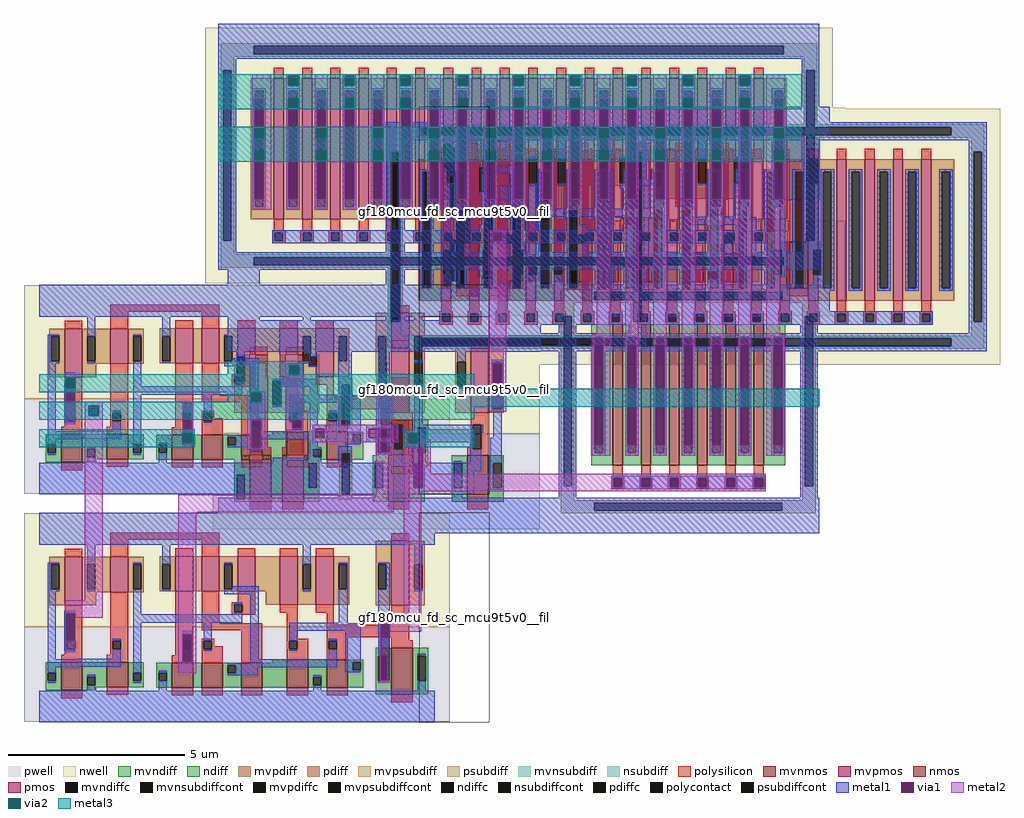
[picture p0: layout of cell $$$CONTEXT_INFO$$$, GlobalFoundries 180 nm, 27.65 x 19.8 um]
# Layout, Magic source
magic
tech gf180mcuD
magscale 1 10
use dff_2ph_clk$1  dff_2ph_clk$1_0
transform 1 0 0 0 1 0
box -2326 -2405 310 103
use gf180mcu_fd_sc_mcu9t5v0__fill_2  gf180mcu_fd_sc_mcu9t5v0__fill_2_0
transform 1 0 0 0 1 0
box -86 -90 310 1098
use gf180mcu_fd_sc_mcu9t5v0__filltie$1  gf180mcu_fd_sc_mcu9t5v0__filltie$1_0
transform 1 0 0 0 1 0
box -86 -90 310 1098
use gf180mcu_fd_sc_mcu9t5v0__filltie  gf180mcu_fd_sc_mcu9t5v0__filltie_0
transform 1 0 0 0 1 0
box -86 -90 310 1098
use gf180mcu_fd_sc_mcu9t5v0__inv_1  gf180mcu_fd_sc_mcu9t5v0__inv_1_0
transform 1 0 0 0 1 0
box -86 -90 534 1098
use gf180mcu_fd_sc_mcu9t5v0__latq_1  gf180mcu_fd_sc_mcu9t5v0__latq_1_0
transform 1 0 0 0 1 0
box -86 -90 2326 1098
use gf180mcu_fd_sc_mcu9t5v0__nand2_1  gf180mcu_fd_sc_mcu9t5v0__nand2_1_0
transform 1 0 0 0 1 0
box -86 -90 646 1098
use nfet  nfet_0
transform 1 0 0 0 1 0
box -268 -284 1200 1010
use pfet  pfet_0
transform 1 0 0 0 1 0
box -352 -362 3204 1086
use tgate$1  tgate$1_0
transform 1 0 0 0 1 0
box -1300 -1318 2256 1570
<< end >>

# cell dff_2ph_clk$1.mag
magic
tech gf180mcuD
magscale 1 10
<< metal1 >>
rect -2240 -90 224 90
rect -2240 -1098 224 -918
<< via1 >>
rect -2089 -635 -2037 -479
rect -1427 -754 -1375 -598
rect -306 -860 -254 -496
rect -2089 -1927 -2037 -1771
rect -1427 -2046 -1375 -1890
rect -306 -2152 -254 -1788
<< metal2 >>
rect -2093 -440 -2037 -406
rect -2093 -496 -2091 -440
rect -330 -496 -230 -484
rect -2093 -635 -2089 -496
rect -2093 -701 -2037 -635
rect -1981 -596 -1881 -574
rect -1981 -652 -1959 -596
rect -1903 -652 -1881 -596
rect -1981 -1698 -1881 -652
rect -1427 -598 -1371 -585
rect -1375 -752 -1371 -598
rect -1373 -808 -1371 -752
rect -1427 -820 -1371 -808
rect -330 -860 -306 -496
rect -254 -860 -230 -496
rect -330 -1100 -230 -860
rect -2093 -1771 -1881 -1698
rect -2093 -1927 -2089 -1771
rect -2037 -1798 -1881 -1771
rect -1451 -1200 -230 -1100
rect -174 -752 -74 -730
rect -174 -808 -152 -752
rect -96 -808 -74 -752
rect -2093 -1993 -2037 -1927
rect -1451 -1890 -1351 -1200
rect -174 -1776 -74 -808
rect -1451 -2046 -1427 -1890
rect -1375 -2046 -1351 -1890
rect -1451 -2112 -1351 -2046
rect -310 -1788 -74 -1776
rect -310 -2152 -306 -1788
rect -254 -1876 -74 -1788
rect -310 -2164 -254 -2152
<< via2 >>
rect -2091 -479 -2035 -440
rect -2091 -496 -2089 -479
rect -2089 -496 -2037 -479
rect -2037 -496 -2035 -479
rect -1959 -652 -1903 -596
rect -1429 -754 -1427 -752
rect -1427 -754 -1375 -752
rect -1375 -754 -1373 -752
rect -1429 -808 -1373 -754
rect -152 -808 -96 -752
<< metal3 >>
rect -2241 -440 224 -418
rect -2241 -496 -2091 -440
rect -2035 -496 224 -440
rect -2241 -518 224 -496
rect -2241 -596 224 -574
rect -2241 -652 -1959 -596
rect -1903 -652 224 -596
rect -2241 -674 224 -652
rect -2241 -752 -1359 -730
rect -2241 -808 -1429 -752
rect -1373 -808 -1359 -752
rect -2241 -830 -1359 -808
rect -174 -752 224 -730
rect -174 -808 -152 -752
rect -96 -808 224 -752
rect -174 -830 224 -808
use gf180mcu_fd_sc_mcu9t5v0__filltie$1  gf180mcu_fd_sc_mcu9t5v0__filltie$1_0
transform 1 0 0 0 1 -2300
box -86 -90 310 1098
use gf180mcu_fd_sc_mcu9t5v0__filltie$1  gf180mcu_fd_sc_mcu9t5v0__filltie$1_1
transform 1 0 0 0 1 -1008
box -86 -90 310 1098
use gf180mcu_fd_sc_mcu9t5v0__latq_1  gf180mcu_fd_sc_mcu9t5v0__latq_1_0
transform 1 0 -2240 0 1 -2300
box -86 -90 2326 1098
use gf180mcu_fd_sc_mcu9t5v0__latq_1  gf180mcu_fd_sc_mcu9t5v0__latq_1_1
transform 1 0 -2240 0 1 -1008
box -86 -90 2326 1098
<< labels >>
flabel metal1 s -2237 -2389 -2237 -2389 2 FreeSans 73 0 0 0 VSSD
port 1 nsew
flabel metal1 s -2237 -1205 -2237 -1205 4 FreeSans 73 0 0 0 VDDD
port 2 nsew
flabel metal1 s -2238 -1096 -2238 -1096 2 FreeSans 73 0 0 0 VSSD
port 1 nsew
flabel metal1 s -2238 88 -2238 88 4 FreeSans 73 0 0 0 VDDD
port 2 nsew
flabel metal3 s 221 -780 221 -780 8 FreeSans 89 0 0 0 Q
port 3 nsew
flabel metal3 s -2239 -468 -2239 -468 2 FreeSans 89 0 0 0 CLK_PH1
port 4 nsew
flabel metal3 s -2239 -624 -2239 -624 2 FreeSans 89 0 0 0 CLK_PH2
port 5 nsew
flabel metal3 s -2239 -780 -2239 -780 2 FreeSans 89 0 0 0 D
port 6 nsew
<< properties >>
string path -11.205 -2.340 1.120 -2.340 
<< end >>

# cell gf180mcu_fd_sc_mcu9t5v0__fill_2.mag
magic
tech gf180mcuD
magscale 1 10
<< nwell >>
rect -86 453 310 1094
<< pwell >>
rect -86 -86 310 453
<< metal1 >>
rect 0 918 224 1098
rect 0 -90 224 90
<< labels >>
flabel metal1 s 102 1000 102 1000 0 FreeSans 400 0 0 0 VDD
port 1 nsew
flabel metal1 s 104 0 104 0 0 FreeSans 400 0 0 0 VSS
port 2 nsew
flabel nwell s 69 784 69 784 0 FreeSans 400 0 0 0 VNW
port 3 nsew
flabel pwell s 68 -17 68 -17 0 FreeSans 400 0 0 0 VPW
port 4 nsew
<< properties >>
string FIXED_BBOX 0 0 224 1008
<< end >>

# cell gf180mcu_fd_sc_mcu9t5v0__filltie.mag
magic
tech gf180mcuD
magscale 1 10
<< nwell >>
rect -86 453 310 1094
<< pwell >>
rect -86 -86 310 453
<< mvpsubdiff >>
rect 72 344 144 357
rect 72 110 85 344
rect 131 110 144 344
rect 72 82 144 110
<< mvnsubdiff >>
rect 72 732 144 771
rect 72 498 85 732
rect 131 498 144 732
rect 72 485 144 498
<< mvpsubdiffcont >>
rect 85 110 131 344
<< mvnsubdiffcont >>
rect 85 498 131 732
<< metal1 >>
rect 0 918 224 1098
rect 66 732 142 918
rect 66 498 85 732
rect 131 498 142 732
rect 66 468 142 498
rect 66 344 142 382
rect 66 110 85 344
rect 131 110 142 344
rect 66 90 142 110
rect 0 -90 224 90
<< labels >>
flabel metal1 s 112 -90 112 -90 0 FreeSans 200 0 0 0 VSS
port 1 nsew
flabel metal1 s 112 1098 112 1098 0 FreeSans 200 0 0 0 VDD
port 2 nsew
<< properties >>
string FIXED_BBOX 0 0 224 1008
<< end >>

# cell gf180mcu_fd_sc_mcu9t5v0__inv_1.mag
magic
tech gf180mcuD
magscale 1 10
<< nwell >>
rect -86 453 534 1094
<< pwell >>
rect -86 -86 534 453
<< mvnmos >>
rect 124 69 244 333
<< mvpmos >>
rect 144 573 244 939
<< mvndiff >>
rect 36 287 124 333
rect 36 147 49 287
rect 95 147 124 287
rect 36 69 124 147
rect 244 287 332 333
rect 244 147 273 287
rect 319 147 332 287
rect 244 69 332 147
<< mvpdiff >>
rect 56 861 144 939
rect 56 721 69 861
rect 115 721 144 861
rect 56 573 144 721
rect 244 861 332 939
rect 244 721 273 861
rect 319 721 332 861
rect 244 573 332 721
<< mvndiffc >>
rect 49 147 95 287
rect 273 147 319 287
<< mvpdiffc >>
rect 69 721 115 861
rect 273 721 319 861
<< polysilicon >>
rect 144 939 244 983
rect 144 506 244 573
rect 144 377 157 506
rect 124 366 157 377
rect 203 366 244 506
rect 124 333 244 366
rect 124 25 244 69
<< polycontact >>
rect 157 366 203 506
<< metal1 >>
rect 0 918 448 1098
rect 69 861 115 918
rect 69 710 115 721
rect 273 861 319 872
rect 142 366 157 506
rect 203 460 214 506
rect 273 430 319 721
rect 49 287 95 298
rect 142 242 203 366
rect 254 287 319 430
rect 49 90 95 147
rect 254 147 273 287
rect 254 136 319 147
rect 0 -90 448 90
<< labels >>
flabel metal1 s 168 392 168 392 0 FreeSans 200 0 0 0 I
port 1 nsew
flabel metal1 s 224 1098 224 1098 0 FreeSans 200 0 0 0 VDD
port 2 nsew
flabel metal1 s 224 -90 224 -90 0 FreeSans 200 0 0 0 VSS
port 3 nsew
flabel metal1 s 280 392 280 392 0 FreeSans 200 0 0 0 ZN
port 4 nsew
flabel nwell s 69 784 69 784 0 FreeSans 400 0 0 0 VNW
port 5 nsew
flabel pwell s 68 -17 68 -17 0 FreeSans 400 0 0 0 VPW
port 6 nsew
<< properties >>
string FIXED_BBOX 0 0 448 1008
<< end >>

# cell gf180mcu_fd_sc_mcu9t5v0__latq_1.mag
magic
tech gf180mcuD
magscale 1 10
<< nwell >>
rect -86 453 2326 1094
<< pwell >>
rect -86 -86 2326 453
<< mvnmos >>
rect 124 92 244 250
rect 384 110 504 250
rect 752 107 872 247
rect 920 107 1040 247
rect 1144 107 1264 247
rect 1404 107 1524 265
rect 1628 107 1748 265
rect 1996 69 2116 333
<< mvpmos >>
rect 144 573 244 849
rect 404 649 504 849
rect 772 652 872 852
rect 920 652 1020 852
rect 1124 652 1224 852
rect 1364 576 1464 852
rect 1568 576 1668 852
rect 1996 573 2096 939
<< mvndiff >>
rect 36 193 124 250
rect 36 147 49 193
rect 95 147 124 193
rect 36 92 124 147
rect 244 168 384 250
rect 244 122 273 168
rect 319 122 384 168
rect 244 110 384 122
rect 504 193 592 250
rect 1908 287 1996 333
rect 1324 247 1404 265
rect 504 147 533 193
rect 579 147 592 193
rect 504 110 592 147
rect 664 193 752 247
rect 664 147 677 193
rect 723 147 752 193
rect 244 92 324 110
rect 664 107 752 147
rect 872 107 920 247
rect 1040 234 1144 247
rect 1040 188 1069 234
rect 1115 188 1144 234
rect 1040 107 1144 188
rect 1264 107 1404 247
rect 1524 166 1628 265
rect 1524 120 1553 166
rect 1599 120 1628 166
rect 1524 107 1628 120
rect 1748 252 1836 265
rect 1748 206 1777 252
rect 1823 206 1836 252
rect 1748 107 1836 206
rect 1908 147 1921 287
rect 1967 147 1996 287
rect 1908 69 1996 147
rect 2116 287 2204 333
rect 2116 147 2145 287
rect 2191 147 2204 287
rect 2116 69 2204 147
<< mvpdiff >>
rect 56 805 144 849
rect 56 665 69 805
rect 115 665 144 805
rect 56 573 144 665
rect 244 805 404 849
rect 244 665 273 805
rect 319 665 404 805
rect 244 649 404 665
rect 504 805 592 849
rect 504 665 533 805
rect 579 665 592 805
rect 504 649 592 665
rect 684 805 772 852
rect 684 665 697 805
rect 743 665 772 805
rect 684 652 772 665
rect 872 652 920 852
rect 1020 805 1124 852
rect 1020 665 1049 805
rect 1095 665 1124 805
rect 1020 652 1124 665
rect 1224 652 1364 852
rect 244 573 324 649
rect 1284 576 1364 652
rect 1464 805 1568 852
rect 1464 665 1493 805
rect 1539 665 1568 805
rect 1464 576 1568 665
rect 1668 805 1756 852
rect 1668 665 1697 805
rect 1743 665 1756 805
rect 1668 576 1756 665
rect 1908 805 1996 939
rect 1908 665 1921 805
rect 1967 665 1996 805
rect 1908 573 1996 665
rect 2096 805 2184 939
rect 2096 665 2125 805
rect 2171 665 2184 805
rect 2096 573 2184 665
<< mvndiffc >>
rect 49 147 95 193
rect 273 122 319 168
rect 533 147 579 193
rect 677 147 723 193
rect 1069 188 1115 234
rect 1553 120 1599 166
rect 1777 206 1823 252
rect 1921 147 1967 287
rect 2145 147 2191 287
<< mvpdiffc >>
rect 69 665 115 805
rect 273 665 319 805
rect 533 665 579 805
rect 697 665 743 805
rect 1049 665 1095 805
rect 1493 665 1539 805
rect 1697 665 1743 805
rect 1921 665 1967 805
rect 2125 665 2171 805
<< polysilicon >>
rect 404 944 1020 984
rect 144 849 244 893
rect 404 849 504 944
rect 772 852 872 896
rect 920 852 1020 944
rect 1996 939 2096 983
rect 1124 852 1224 896
rect 1364 852 1464 896
rect 1568 852 1668 896
rect 144 372 244 573
rect 144 326 157 372
rect 203 326 244 372
rect 144 294 244 326
rect 404 372 504 649
rect 404 326 417 372
rect 463 326 504 372
rect 404 294 504 326
rect 124 250 244 294
rect 384 250 504 294
rect 772 372 872 652
rect 920 472 1020 652
rect 1124 608 1224 652
rect 1124 592 1223 608
rect 1092 579 1223 592
rect 1092 533 1105 579
rect 1151 533 1223 579
rect 1092 520 1223 533
rect 1364 532 1464 576
rect 1568 532 1668 576
rect 920 433 1264 472
rect 1011 432 1264 433
rect 772 326 813 372
rect 859 326 872 372
rect 772 291 872 326
rect 752 247 872 291
rect 920 372 992 385
rect 920 326 933 372
rect 979 343 992 372
rect 979 326 1040 343
rect 920 247 1040 326
rect 1144 247 1264 432
rect 1404 385 1464 532
rect 1628 465 1668 532
rect 1996 465 2096 573
rect 1628 393 2096 465
rect 1404 372 1524 385
rect 1404 326 1417 372
rect 1463 326 1524 372
rect 1404 265 1524 326
rect 1628 372 1748 393
rect 1628 326 1641 372
rect 1687 326 1748 372
rect 1996 377 2096 393
rect 1996 333 2116 377
rect 1628 265 1748 326
rect 124 48 244 92
rect 384 66 504 110
rect 752 63 872 107
rect 920 63 1040 107
rect 1144 63 1264 107
rect 1404 63 1524 107
rect 1628 63 1748 107
rect 1996 25 2116 69
<< polycontact >>
rect 157 326 203 372
rect 417 326 463 372
rect 1105 533 1151 579
rect 813 326 859 372
rect 933 326 979 372
rect 1417 326 1463 372
rect 1641 326 1687 372
<< metal1 >>
rect 0 918 2240 1098
rect 49 805 115 816
rect 49 665 69 805
rect 49 654 115 665
rect 273 805 319 918
rect 273 654 319 665
rect 533 805 579 816
rect 49 269 95 654
rect 142 372 203 542
rect 533 522 579 665
rect 697 805 743 918
rect 697 654 743 665
rect 1049 805 1095 816
rect 1493 805 1539 918
rect 1095 665 1243 682
rect 1049 636 1243 665
rect 1493 654 1539 665
rect 1697 805 1747 816
rect 1743 665 1747 805
rect 1105 579 1151 590
rect 1105 522 1151 533
rect 533 476 1151 522
rect 142 326 157 372
rect 142 315 203 326
rect 417 372 463 383
rect 417 271 463 326
rect 217 269 463 271
rect 49 225 463 269
rect 49 223 231 225
rect 49 193 95 223
rect 533 193 579 476
rect 813 372 866 430
rect 859 326 866 372
rect 813 242 866 326
rect 933 372 979 476
rect 933 315 979 326
rect 1197 269 1243 636
rect 1697 475 1747 665
rect 1417 473 1747 475
rect 1921 805 1986 816
rect 1967 665 1986 805
rect 1417 429 1823 473
rect 1417 372 1463 429
rect 1417 315 1463 326
rect 1641 372 1687 383
rect 1641 269 1687 326
rect 1197 245 1687 269
rect 1069 234 1687 245
rect 49 136 95 147
rect 273 168 319 179
rect 533 136 579 147
rect 677 193 723 204
rect 1115 223 1687 234
rect 1733 252 1823 429
rect 1115 188 1238 223
rect 1733 206 1777 252
rect 1733 195 1823 206
rect 1921 287 1986 665
rect 2125 805 2171 918
rect 2125 654 2171 665
rect 1069 177 1238 188
rect 273 90 319 122
rect 677 90 723 147
rect 1553 166 1599 177
rect 1967 147 1986 287
rect 1921 136 1986 147
rect 2145 287 2191 298
rect 1553 90 1599 120
rect 2145 90 2191 147
rect 0 -90 2240 90
<< labels >>
flabel metal1 s 840 280 840 280 0 FreeSans 200 0 0 0 D
port 1 nsew
flabel metal1 s 168 392 168 392 0 FreeSans 200 0 0 0 E
port 2 nsew
flabel metal1 s 1960 504 1960 504 0 FreeSans 200 0 0 0 Q
port 3 nsew
flabel metal1 s 1120 1098 1120 1098 0 FreeSans 200 0 0 0 VDD
port 4 nsew
flabel metal1 s 1120 -90 1120 -90 0 FreeSans 200 0 0 0 VSS
port 5 nsew
flabel nwell s 69 784 69 784 0 FreeSans 400 0 0 0 VNW
port 6 nsew
flabel pwell s 68 -17 68 -17 0 FreeSans 400 0 0 0 VPW
port 7 nsew
<< properties >>
string FIXED_BBOX 0 0 2240 1008
<< end >>

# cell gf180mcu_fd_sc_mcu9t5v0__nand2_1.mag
magic
tech gf180mcuD
magscale 1 10
<< nwell >>
rect -86 453 646 1094
<< pwell >>
rect -86 -86 646 453
<< mvnmos >>
rect 125 69 245 333
rect 309 69 429 333
<< mvpmos >>
rect 125 573 225 902
rect 329 573 429 902
<< mvndiff >>
rect 37 222 125 333
rect 37 82 50 222
rect 96 82 125 222
rect 37 69 125 82
rect 245 69 309 333
rect 429 287 517 333
rect 429 147 458 287
rect 504 147 517 287
rect 429 69 517 147
<< mvpdiff >>
rect 37 889 125 902
rect 37 749 50 889
rect 96 749 125 889
rect 37 573 125 749
rect 225 755 329 902
rect 225 615 254 755
rect 300 615 329 755
rect 225 573 329 615
rect 429 889 517 902
rect 429 843 458 889
rect 504 843 517 889
rect 429 573 517 843
<< mvndiffc >>
rect 50 82 96 222
rect 458 147 504 287
<< mvpdiffc >>
rect 50 749 96 889
rect 254 615 300 755
rect 458 843 504 889
<< polysilicon >>
rect 125 902 225 946
rect 329 902 429 946
rect 125 540 225 573
rect 125 494 138 540
rect 184 494 225 540
rect 125 377 225 494
rect 329 523 429 573
rect 329 477 366 523
rect 412 477 429 523
rect 329 377 429 477
rect 125 333 245 377
rect 309 333 429 377
rect 125 25 245 69
rect 309 25 429 69
<< polycontact >>
rect 138 494 184 540
rect 366 477 412 523
<< metal1 >>
rect 0 918 560 1098
rect 50 889 96 918
rect 458 889 504 918
rect 458 832 504 843
rect 50 738 96 749
rect 254 755 510 766
rect 300 720 510 755
rect 300 615 306 720
rect 254 604 306 615
rect 127 540 195 542
rect 127 494 138 540
rect 184 494 195 540
rect 127 354 195 494
rect 366 523 418 654
rect 412 477 418 523
rect 366 466 418 477
rect 464 318 510 720
rect 254 287 510 318
rect 254 242 458 287
rect 50 222 96 233
rect 0 82 50 90
rect 504 147 510 287
rect 458 136 510 147
rect 96 82 560 90
rect 0 -90 560 82
<< labels >>
flabel metal1 s 392 504 392 504 0 FreeSans 200 0 0 0 A1
port 1 nsew
flabel metal1 s 168 392 168 392 0 FreeSans 200 0 0 0 A2
port 2 nsew
flabel metal1 s 280 1098 280 1098 0 FreeSans 200 0 0 0 VDD
port 3 nsew
flabel metal1 s 280 -90 280 -90 0 FreeSans 200 0 0 0 VSS
port 4 nsew
flabel metal1 s 392 280 392 280 0 FreeSans 200 0 0 0 ZN
port 5 nsew
flabel nwell s 69 784 69 784 0 FreeSans 400 0 0 0 VNW
port 6 nsew
flabel pwell s 68 -17 68 -17 0 FreeSans 400 0 0 0 VPW
port 7 nsew
<< properties >>
string FIXED_BBOX 0 0 560 1008
<< end >>

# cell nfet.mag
magic
tech gf180mcuD
magscale 1 10
<< nmos >>
rect 38 0 94 800
rect 198 0 254 800
rect 358 0 414 800
rect 518 0 574 800
rect 678 0 734 800
rect 838 0 894 800
<< ndiff >>
rect -84 729 38 800
rect -84 71 -65 729
rect -19 71 38 729
rect -84 0 38 71
rect 94 729 198 800
rect 94 71 123 729
rect 169 71 198 729
rect 94 0 198 71
rect 254 729 358 800
rect 254 71 283 729
rect 329 71 358 729
rect 254 0 358 71
rect 414 729 518 800
rect 414 71 443 729
rect 489 71 518 729
rect 414 0 518 71
rect 574 729 678 800
rect 574 71 603 729
rect 649 71 678 729
rect 574 0 678 71
rect 734 729 838 800
rect 734 71 763 729
rect 809 71 838 729
rect 734 0 838 71
rect 894 729 1016 800
rect 894 71 951 729
rect 997 71 1016 729
rect 894 0 1016 71
<< ndiffc >>
rect -65 71 -19 729
rect 123 71 169 729
rect 283 71 329 729
rect 443 71 489 729
rect 603 71 649 729
rect 763 71 809 729
rect 951 71 997 729
<< psubdiff >>
rect -256 983 1188 998
rect -256 937 -67 983
rect 999 937 1188 983
rect -256 922 1188 937
rect -256 845 -180 922
rect -256 -119 -241 845
rect -195 -119 -180 845
rect 1112 845 1188 922
rect -256 -196 -180 -119
rect 1112 -119 1127 845
rect 1173 -119 1188 845
rect 1112 -196 1188 -119
rect -256 -211 1188 -196
rect -256 -257 -67 -211
rect 999 -257 1188 -211
rect -256 -272 1188 -257
<< psubdiffcont >>
rect -67 937 999 983
rect -241 -119 -195 845
rect 1127 -119 1173 845
rect -67 -257 999 -211
<< polysilicon >>
rect 38 800 94 860
rect 198 800 254 860
rect 358 800 414 860
rect 518 800 574 860
rect 678 800 734 860
rect 838 800 894 860
rect 38 -60 94 0
rect 198 -60 254 0
rect 358 -60 414 0
rect 518 -60 574 0
rect 678 -60 734 0
rect 838 -60 894 0
rect 30 -73 102 -60
rect 30 -119 43 -73
rect 89 -119 102 -73
rect 30 -132 102 -119
rect 190 -73 262 -60
rect 190 -119 203 -73
rect 249 -119 262 -73
rect 190 -132 262 -119
rect 350 -73 422 -60
rect 350 -119 363 -73
rect 409 -119 422 -73
rect 350 -132 422 -119
rect 510 -73 582 -60
rect 510 -119 523 -73
rect 569 -119 582 -73
rect 510 -132 582 -119
rect 670 -73 742 -60
rect 670 -119 683 -73
rect 729 -119 742 -73
rect 670 -132 742 -119
rect 830 -73 902 -60
rect 830 -119 843 -73
rect 889 -119 902 -73
rect 830 -132 902 -119
<< polycontact >>
rect 43 -119 89 -73
rect 203 -119 249 -73
rect 363 -119 409 -73
rect 523 -119 569 -73
rect 683 -119 729 -73
rect 843 -119 889 -73
<< metal1 >>
rect -268 983 1200 1010
rect -268 937 -67 983
rect 999 937 1200 983
rect -268 910 1200 937
rect -268 845 -168 910
rect -268 -119 -241 845
rect -195 -119 -168 845
rect 1100 845 1200 910
rect -80 729 -4 744
rect -80 71 -65 729
rect -19 71 -4 729
rect -80 56 -4 71
rect 108 729 184 744
rect 108 71 123 729
rect 169 71 184 729
rect 108 56 184 71
rect 268 729 344 744
rect 268 71 283 729
rect 329 71 344 729
rect 268 56 344 71
rect 428 729 504 744
rect 428 71 443 729
rect 489 71 504 729
rect 428 56 504 71
rect 588 729 664 744
rect 588 71 603 729
rect 649 71 664 729
rect 588 56 664 71
rect 748 729 824 744
rect 748 71 763 729
rect 809 71 824 729
rect 748 56 824 71
rect 936 729 1012 744
rect 936 71 951 729
rect 997 71 1012 729
rect 936 56 1012 71
rect -268 -184 -168 -119
rect 28 -73 904 -58
rect 28 -119 43 -73
rect 89 -119 203 -73
rect 249 -119 363 -73
rect 409 -119 523 -73
rect 569 -119 683 -73
rect 729 -119 843 -73
rect 889 -119 904 -73
rect 28 -134 904 -119
rect 1100 -119 1127 845
rect 1173 -119 1200 845
rect 1100 -184 1200 -119
rect -268 -211 1200 -184
rect -268 -257 -67 -211
rect 999 -257 1200 -211
rect -268 -284 1200 -257
<< labels >>
flabel metal1 s 44 -118 44 -118 2 FreeSans 73 0 0 0 G
port 1 nsew
flabel metal1 s -218 -234 -218 -234 2 FreeSans 73 0 0 0 B
port 2 nsew
flabel metal1 s 124 72 124 72 2 FreeSans 73 0 0 0 D
port 3 nsew
flabel metal1 s -64 72 -64 72 2 FreeSans 73 0 0 0 S
port 4 nsew
flabel metal1 s 284 72 284 72 2 FreeSans 73 0 0 0 S
port 4 nsew
flabel metal1 s 952 72 952 72 2 FreeSans 73 0 0 0 S
port 4 nsew
flabel metal1 s 604 72 604 72 2 FreeSans 73 0 0 0 S
port 4 nsew
flabel metal1 s 444 72 444 72 2 FreeSans 73 0 0 0 D
port 3 nsew
flabel metal1 s 764 72 764 72 2 FreeSans 73 0 0 0 D
port 3 nsew
<< properties >>
string path -1.340 4.800 5.750 4.800 5.750 -1.170 -1.090 -1.170 -1.090 4.550 
<< end >>

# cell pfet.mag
magic
tech gf180mcuD
magscale 1 10
<< nwell >>
rect -352 -362 3204 1086
<< pmos >>
rect 38 0 94 800
rect 198 0 254 800
rect 358 0 414 800
rect 518 0 574 800
rect 678 0 734 800
rect 838 0 894 800
rect 998 0 1054 800
rect 1158 0 1214 800
rect 1318 0 1374 800
rect 1478 0 1534 800
rect 1638 0 1694 800
rect 1798 0 1854 800
rect 1958 0 2014 800
rect 2118 0 2174 800
rect 2278 0 2334 800
rect 2438 0 2494 800
rect 2598 0 2654 800
rect 2758 0 2814 800
<< pdiff >>
rect -92 729 38 800
rect -92 71 -69 729
rect -23 71 38 729
rect -92 0 38 71
rect 94 729 198 800
rect 94 71 123 729
rect 169 71 198 729
rect 94 0 198 71
rect 254 729 358 800
rect 254 71 283 729
rect 329 71 358 729
rect 254 0 358 71
rect 414 729 518 800
rect 414 71 443 729
rect 489 71 518 729
rect 414 0 518 71
rect 574 729 678 800
rect 574 71 603 729
rect 649 71 678 729
rect 574 0 678 71
rect 734 729 838 800
rect 734 71 763 729
rect 809 71 838 729
rect 734 0 838 71
rect 894 729 998 800
rect 894 71 923 729
rect 969 71 998 729
rect 894 0 998 71
rect 1054 729 1158 800
rect 1054 71 1083 729
rect 1129 71 1158 729
rect 1054 0 1158 71
rect 1214 729 1318 800
rect 1214 71 1243 729
rect 1289 71 1318 729
rect 1214 0 1318 71
rect 1374 729 1478 800
rect 1374 71 1403 729
rect 1449 71 1478 729
rect 1374 0 1478 71
rect 1534 729 1638 800
rect 1534 71 1563 729
rect 1609 71 1638 729
rect 1534 0 1638 71
rect 1694 729 1798 800
rect 1694 71 1723 729
rect 1769 71 1798 729
rect 1694 0 1798 71
rect 1854 729 1958 800
rect 1854 71 1883 729
rect 1929 71 1958 729
rect 1854 0 1958 71
rect 2014 729 2118 800
rect 2014 71 2043 729
rect 2089 71 2118 729
rect 2014 0 2118 71
rect 2174 729 2278 800
rect 2174 71 2203 729
rect 2249 71 2278 729
rect 2174 0 2278 71
rect 2334 729 2438 800
rect 2334 71 2363 729
rect 2409 71 2438 729
rect 2334 0 2438 71
rect 2494 729 2598 800
rect 2494 71 2523 729
rect 2569 71 2598 729
rect 2494 0 2598 71
rect 2654 729 2758 800
rect 2654 71 2683 729
rect 2729 71 2758 729
rect 2654 0 2758 71
rect 2814 729 2944 800
rect 2814 71 2875 729
rect 2921 71 2944 729
rect 2814 0 2944 71
<< pdiffc >>
rect -69 71 -23 729
rect 123 71 169 729
rect 283 71 329 729
rect 443 71 489 729
rect 603 71 649 729
rect 763 71 809 729
rect 923 71 969 729
rect 1083 71 1129 729
rect 1243 71 1289 729
rect 1403 71 1449 729
rect 1563 71 1609 729
rect 1723 71 1769 729
rect 1883 71 1929 729
rect 2043 71 2089 729
rect 2203 71 2249 729
rect 2363 71 2409 729
rect 2523 71 2569 729
rect 2683 71 2729 729
rect 2875 71 2921 729
<< nsubdiff >>
rect -264 983 3116 998
rect -264 937 -76 983
rect 2928 937 3116 983
rect -264 922 3116 937
rect -264 844 -188 922
rect -264 -120 -249 844
rect -203 -120 -188 844
rect 3040 844 3116 922
rect -264 -198 -188 -120
rect 3040 -120 3055 844
rect 3101 -120 3116 844
rect 3040 -198 3116 -120
rect -264 -213 3116 -198
rect -264 -259 -76 -213
rect 2928 -259 3116 -213
rect -264 -274 3116 -259
<< nsubdiffcont >>
rect -76 937 2928 983
rect -249 -120 -203 844
rect 3055 -120 3101 844
rect -76 -259 2928 -213
<< polysilicon >>
rect 38 800 94 860
rect 198 800 254 860
rect 358 800 414 860
rect 518 800 574 860
rect 678 800 734 860
rect 838 800 894 860
rect 998 800 1054 860
rect 1158 800 1214 860
rect 1318 800 1374 860
rect 1478 800 1534 860
rect 1638 800 1694 860
rect 1798 800 1854 860
rect 1958 800 2014 860
rect 2118 800 2174 860
rect 2278 800 2334 860
rect 2438 800 2494 860
rect 2598 800 2654 860
rect 2758 800 2814 860
rect 38 -60 94 0
rect 198 -60 254 0
rect 358 -60 414 0
rect 518 -60 574 0
rect 678 -60 734 0
rect 838 -60 894 0
rect 998 -60 1054 0
rect 1158 -60 1214 0
rect 1318 -60 1374 0
rect 1478 -60 1534 0
rect 1638 -60 1694 0
rect 1798 -60 1854 0
rect 1958 -60 2014 0
rect 2118 -60 2174 0
rect 2278 -60 2334 0
rect 2438 -60 2494 0
rect 2598 -60 2654 0
rect 2758 -60 2814 0
rect 28 -75 104 -60
rect 28 -121 43 -75
rect 89 -121 104 -75
rect 28 -136 104 -121
rect 188 -75 264 -60
rect 188 -121 203 -75
rect 249 -121 264 -75
rect 188 -136 264 -121
rect 348 -75 424 -60
rect 348 -121 363 -75
rect 409 -121 424 -75
rect 348 -136 424 -121
rect 508 -75 584 -60
rect 508 -121 523 -75
rect 569 -121 584 -75
rect 508 -136 584 -121
rect 668 -75 744 -60
rect 668 -121 683 -75
rect 729 -121 744 -75
rect 668 -136 744 -121
rect 828 -75 904 -60
rect 828 -121 843 -75
rect 889 -121 904 -75
rect 828 -136 904 -121
rect 988 -75 1064 -60
rect 988 -121 1003 -75
rect 1049 -121 1064 -75
rect 988 -136 1064 -121
rect 1148 -75 1224 -60
rect 1148 -121 1163 -75
rect 1209 -121 1224 -75
rect 1148 -136 1224 -121
rect 1308 -75 1384 -60
rect 1308 -121 1323 -75
rect 1369 -121 1384 -75
rect 1308 -136 1384 -121
rect 1468 -75 1544 -60
rect 1468 -121 1483 -75
rect 1529 -121 1544 -75
rect 1468 -136 1544 -121
rect 1628 -75 1704 -60
rect 1628 -121 1643 -75
rect 1689 -121 1704 -75
rect 1628 -136 1704 -121
rect 1788 -75 1864 -60
rect 1788 -121 1803 -75
rect 1849 -121 1864 -75
rect 1788 -136 1864 -121
rect 1948 -75 2024 -60
rect 1948 -121 1963 -75
rect 2009 -121 2024 -75
rect 1948 -136 2024 -121
rect 2108 -75 2184 -60
rect 2108 -121 2123 -75
rect 2169 -121 2184 -75
rect 2108 -136 2184 -121
rect 2268 -75 2344 -60
rect 2268 -121 2283 -75
rect 2329 -121 2344 -75
rect 2268 -136 2344 -121
rect 2428 -75 2504 -60
rect 2428 -121 2443 -75
rect 2489 -121 2504 -75
rect 2428 -136 2504 -121
rect 2588 -75 2664 -60
rect 2588 -121 2603 -75
rect 2649 -121 2664 -75
rect 2588 -136 2664 -121
rect 2748 -75 2824 -60
rect 2748 -121 2763 -75
rect 2809 -121 2824 -75
rect 2748 -136 2824 -121
<< polycontact >>
rect 43 -121 89 -75
rect 203 -121 249 -75
rect 363 -121 409 -75
rect 523 -121 569 -75
rect 683 -121 729 -75
rect 843 -121 889 -75
rect 1003 -121 1049 -75
rect 1163 -121 1209 -75
rect 1323 -121 1369 -75
rect 1483 -121 1529 -75
rect 1643 -121 1689 -75
rect 1803 -121 1849 -75
rect 1963 -121 2009 -75
rect 2123 -121 2169 -75
rect 2283 -121 2329 -75
rect 2443 -121 2489 -75
rect 2603 -121 2649 -75
rect 2763 -121 2809 -75
<< metal1 >>
rect -276 983 3128 1010
rect -276 937 -76 983
rect 2928 937 3128 983
rect -276 910 3128 937
rect -276 844 -176 910
rect -276 -120 -249 844
rect -203 -120 -176 844
rect 3028 844 3128 910
rect -84 729 -8 744
rect -84 71 -69 729
rect -23 71 -8 729
rect -84 56 -8 71
rect 108 729 184 744
rect 108 71 123 729
rect 169 71 184 729
rect 108 56 184 71
rect 268 729 344 744
rect 268 71 283 729
rect 329 71 344 729
rect 268 56 344 71
rect 428 729 504 744
rect 428 71 443 729
rect 489 71 504 729
rect 428 56 504 71
rect 588 729 664 744
rect 588 71 603 729
rect 649 71 664 729
rect 588 56 664 71
rect 748 729 824 744
rect 748 71 763 729
rect 809 71 824 729
rect 748 56 824 71
rect 908 729 984 744
rect 908 71 923 729
rect 969 71 984 729
rect 908 56 984 71
rect 1068 729 1144 744
rect 1068 71 1083 729
rect 1129 71 1144 729
rect 1068 56 1144 71
rect 1228 729 1304 744
rect 1228 71 1243 729
rect 1289 71 1304 729
rect 1228 56 1304 71
rect 1388 729 1464 744
rect 1388 71 1403 729
rect 1449 71 1464 729
rect 1388 56 1464 71
rect 1548 729 1624 744
rect 1548 71 1563 729
rect 1609 71 1624 729
rect 1548 56 1624 71
rect 1708 729 1784 744
rect 1708 71 1723 729
rect 1769 71 1784 729
rect 1708 56 1784 71
rect 1868 729 1944 744
rect 1868 71 1883 729
rect 1929 71 1944 729
rect 1868 56 1944 71
rect 2028 729 2104 744
rect 2028 71 2043 729
rect 2089 71 2104 729
rect 2028 56 2104 71
rect 2188 729 2264 744
rect 2188 71 2203 729
rect 2249 71 2264 729
rect 2188 56 2264 71
rect 2348 729 2424 744
rect 2348 71 2363 729
rect 2409 71 2424 729
rect 2348 56 2424 71
rect 2508 729 2584 744
rect 2508 71 2523 729
rect 2569 71 2584 729
rect 2508 56 2584 71
rect 2668 729 2744 744
rect 2668 71 2683 729
rect 2729 71 2744 729
rect 2668 56 2744 71
rect 2860 729 2936 744
rect 2860 71 2875 729
rect 2921 71 2936 729
rect 2860 56 2936 71
rect -276 -186 -176 -120
rect 28 -75 2824 -60
rect 28 -121 43 -75
rect 89 -121 203 -75
rect 249 -121 363 -75
rect 409 -121 523 -75
rect 569 -121 683 -75
rect 729 -121 843 -75
rect 889 -121 1003 -75
rect 1049 -121 1163 -75
rect 1209 -121 1323 -75
rect 1369 -121 1483 -75
rect 1529 -121 1643 -75
rect 1689 -121 1803 -75
rect 1849 -121 1963 -75
rect 2009 -121 2123 -75
rect 2169 -121 2283 -75
rect 2329 -121 2443 -75
rect 2489 -121 2603 -75
rect 2649 -121 2763 -75
rect 2809 -121 2824 -75
rect 28 -136 2824 -121
rect 3028 -120 3055 844
rect 3101 -120 3128 844
rect 3028 -186 3128 -120
rect -276 -213 3128 -186
rect -276 -259 -76 -213
rect 2928 -259 3128 -213
rect -276 -286 3128 -259
<< labels >>
flabel metal1 s 44 -120 44 -120 2 FreeSans 73 0 0 0 G
port 1 nsew
flabel metal1 s -68 72 -68 72 2 FreeSans 73 0 0 0 S
port 2 nsew
flabel metal1 s 2876 72 2876 72 2 FreeSans 73 0 0 0 S
port 2 nsew
flabel metal1 s 2524 72 2524 72 2 FreeSans 73 0 0 0 S
port 2 nsew
flabel metal1 s 2204 72 2204 72 2 FreeSans 73 0 0 0 S
port 2 nsew
flabel metal1 s 1884 72 1884 72 2 FreeSans 73 0 0 0 S
port 2 nsew
flabel metal1 s 1564 73 1564 73 2 FreeSans 73 0 0 0 S
port 2 nsew
flabel metal1 s 1244 73 1244 73 2 FreeSans 73 0 0 0 S
port 2 nsew
flabel metal1 s 924 72 924 72 2 FreeSans 73 0 0 0 S
port 2 nsew
flabel metal1 s 604 72 604 72 2 FreeSans 73 0 0 0 S
port 2 nsew
flabel metal1 s 284 73 284 73 2 FreeSans 73 0 0 0 S
port 2 nsew
flabel metal1 s 2044 71 2044 71 2 FreeSans 73 0 0 0 D
port 3 nsew
flabel metal1 s 1724 71 1724 71 2 FreeSans 73 0 0 0 D
port 3 nsew
flabel metal1 s 1404 72 1404 72 2 FreeSans 73 0 0 0 D
port 3 nsew
flabel metal1 s 1084 72 1084 72 2 FreeSans 73 0 0 0 D
port 3 nsew
flabel metal1 s 764 71 764 71 2 FreeSans 73 0 0 0 D
port 3 nsew
flabel metal1 s 444 71 444 71 2 FreeSans 73 0 0 0 D
port 3 nsew
flabel metal1 s 124 72 124 72 2 FreeSans 73 0 0 0 D
port 3 nsew
flabel metal1 s 2364 71 2364 71 2 FreeSans 73 0 0 0 D
port 3 nsew
flabel metal1 s 2684 72 2684 72 2 FreeSans 73 0 0 0 D
port 3 nsew
flabel metal1 s -226 -236 -226 -236 2 FreeSans 73 0 0 0 B
port 4 nsew
<< properties >>
string path -1.490 4.800 15.390 4.800 15.390 -1.180 -1.130 -1.180 -1.130 4.440 
<< end >>

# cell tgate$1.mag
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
